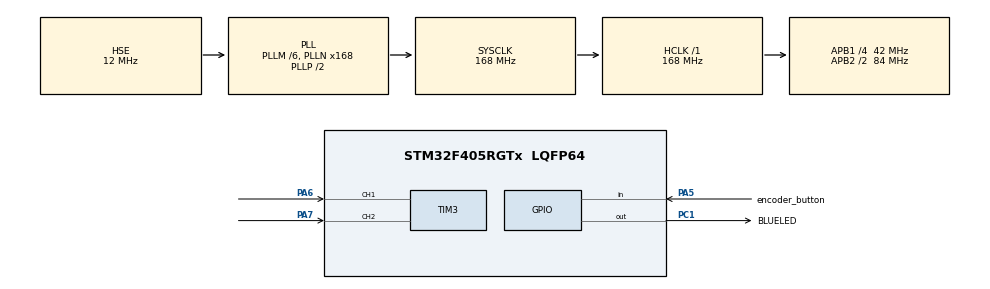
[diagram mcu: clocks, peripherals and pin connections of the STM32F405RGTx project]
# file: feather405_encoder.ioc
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Mcu.Family=STM32F4
Mcu.Name=STM32F405RGTx
Mcu.Package=LQFP64
NVIC.PriorityGroup=NVIC_PRIORITYGROUP_4
PA13.Mode=Serial_Wire
PA13.Signal=SYS_JTMS-SWDIO
PA14.Mode=Serial_Wire
PA14.Signal=SYS_JTCK-SWCLK
PA5.GPIO_Label=encoder_button
PA5.GPIO_PuPd=GPIO_PULLUP
PA5.Signal=GPIO_Input
PA6.Signal=S_TIM3_CH1
PA7.Signal=S_TIM3_CH2
PC1.GPIO_Label=BLUELED
PC1.Signal=GPIO_Output
PH0-OSC_IN.Mode=HSE-External-Oscillator
PH0-OSC_IN.Signal=RCC_OSC_IN
PH1-OSC_OUT.Mode=HSE-External-Oscillator
PH1-OSC_OUT.Signal=RCC_OSC_OUT
ProjectManager.HeapSize=0x200
ProjectManager.StackSize=0x400
ProjectManager.TargetToolchain=STM32CubeIDE
RCC.48MHZClocksFreq_Value=84000000
RCC.AHBFreq_Value=168000000
RCC.APB1CLKDivider=RCC_HCLK_DIV4
RCC.APB1Freq_Value=42000000
RCC.APB1TimFreq_Value=84000000
RCC.APB2CLKDivider=RCC_HCLK_DIV2
RCC.APB2Freq_Value=84000000
RCC.APB2TimFreq_Value=168000000
RCC.CortexFreq_Value=168000000
RCC.HCLKFreq_Value=168000000
RCC.HSE_VALUE=12000000
RCC.HSI_VALUE=16000000
RCC.LSE_VALUE=32768
RCC.PLLM=6
RCC.PLLN=168
RCC.PLLSourceVirtual=RCC_PLLSOURCE_HSE
RCC.SYSCLKFreq_VALUE=168000000
RCC.SYSCLKSource=RCC_SYSCLKSOURCE_PLLCLK
RCC.VCOOutputFreq_Value=336000000
SH.S_TIM3_CH1.0=TIM3_CH1,Encoder_Interface
SH.S_TIM3_CH2.0=TIM3_CH2,Encoder_Interface
TIM3.EncoderMode=TIM_ENCODERMODE_TI12
TIM3.IC1Polarity=TIM_ICPOLARITY_FALLING
TIM3.IC2Polarity=TIM_ICPOLARITY_FALLING
board=custom

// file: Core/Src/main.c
/* USER CODE BEGIN Header */
/**
  ******************************************************************************
  * @file           : main.c
  * @brief          : Main program body
  ******************************************************************************
  * @attention
  *
  * Copyright (c) 2023 STMicroelectronics.
  * All rights reserved.
  *
  * This software is licensed under terms that can be found in the LICENSE file
  * in the root directory of this software component.
  * If no LICENSE file comes with this software, it is provided AS-IS.
  *
  ******************************************************************************
  */
/* USER CODE END Header */
#include "main.h"

TIM_HandleTypeDef htim3;

void SystemClock_Config(void);
static void MX_GPIO_Init(void);
static void MX_TIM3_Init(void);

/* USER CODE BEGIN 0 */
int16_t counter=0;
/* USER CODE END 0 */

int main(void)
{

  /* MCU Configuration--------------------------------------------------------*/

  /* Reset of all peripherals, Initializes the Flash interface and the Systick. */
  HAL_Init();

  /* Configure the system clock */
  SystemClock_Config();

  /* Initialize all configured peripherals */
  MX_GPIO_Init();
  MX_TIM3_Init();
  /* USER CODE BEGIN 2 */
HAL_TIM_Encoder_Start(&htim3, TIM_CHANNEL_ALL);
  /* USER CODE END 2 */

  /* Infinite loop */
  /* USER CODE BEGIN WHILE */
  while (1)
  {
	  if(HAL_GPIO_ReadPin(encoder_button_GPIO_Port, encoder_button_Pin)==GPIO_PIN_SET){//https://www.youtube.com/watch?v=xqzWQgpqHmI
		  HAL_GPIO_WritePin(BLUELED_GPIO_Port, BLUELED_Pin, GPIO_PIN_RESET);
	  }else{
		  HAL_GPIO_WritePin(BLUELED_GPIO_Port, BLUELED_Pin, GPIO_PIN_SET);
	  }
	  counter=htim3.Instance->CNT;

    /* USER CODE END WHILE */

  }
}

void SystemClock_Config(void)
{
  RCC_OscInitTypeDef RCC_OscInitStruct = {0};
  RCC_ClkInitTypeDef RCC_ClkInitStruct = {0};

  /** Configure the main internal regulator output voltage
  */
  __HAL_RCC_PWR_CLK_ENABLE();
  __HAL_PWR_VOLTAGESCALING_CONFIG(PWR_REGULATOR_VOLTAGE_SCALE1);

  /** Initializes the RCC Oscillators according to the specified parameters
  * in the RCC_OscInitTypeDef structure.
  */
  RCC_OscInitStruct.OscillatorType = RCC_OSCILLATORTYPE_HSE;
  RCC_OscInitStruct.HSEState = RCC_HSE_ON;
  RCC_OscInitStruct.PLL.PLLState = RCC_PLL_ON;
  RCC_OscInitStruct.PLL.PLLSource = RCC_PLLSOURCE_HSE;
  RCC_OscInitStruct.PLL.PLLM = 6;
  RCC_OscInitStruct.PLL.PLLN = 168;
  RCC_OscInitStruct.PLL.PLLP = RCC_PLLP_DIV2;
  RCC_OscInitStruct.PLL.PLLQ = 4;
  if (HAL_RCC_OscConfig(&RCC_OscInitStruct) != HAL_OK)
  {
    Error_Handler();
  }

  /** Initializes the CPU, AHB and APB buses clocks
  */
  RCC_ClkInitStruct.ClockType = RCC_CLOCKTYPE_HCLK|RCC_CLOCKTYPE_SYSCLK
                              |RCC_CLOCKTYPE_PCLK1|RCC_CLOCKTYPE_PCLK2;
  RCC_ClkInitStruct.SYSCLKSource = RCC_SYSCLKSOURCE_PLLCLK;
  RCC_ClkInitStruct.AHBCLKDivider = RCC_SYSCLK_DIV1;
  RCC_ClkInitStruct.APB1CLKDivider = RCC_HCLK_DIV4;
  RCC_ClkInitStruct.APB2CLKDivider = RCC_HCLK_DIV2;

  if (HAL_RCC_ClockConfig(&RCC_ClkInitStruct, FLASH_LATENCY_5) != HAL_OK)
  {
    Error_Handler();
  }
}

static void MX_TIM3_Init(void)
{

  TIM_Encoder_InitTypeDef sConfig = {0};
  TIM_MasterConfigTypeDef sMasterConfig = {0};

  htim3.Instance = TIM3;
  htim3.Init.Prescaler = 0;
  htim3.Init.CounterMode = TIM_COUNTERMODE_UP;
  htim3.Init.Period = 65535;
  htim3.Init.ClockDivision = TIM_CLOCKDIVISION_DIV1;
  htim3.Init.AutoReloadPreload = TIM_AUTORELOAD_PRELOAD_DISABLE;
  sConfig.EncoderMode = TIM_ENCODERMODE_TI12;
  sConfig.IC1Polarity = TIM_ICPOLARITY_FALLING;
  sConfig.IC1Selection = TIM_ICSELECTION_DIRECTTI;
  sConfig.IC1Prescaler = TIM_ICPSC_DIV1;
  sConfig.IC1Filter = 0;
  sConfig.IC2Polarity = TIM_ICPOLARITY_FALLING;
  sConfig.IC2Selection = TIM_ICSELECTION_DIRECTTI;
  sConfig.IC2Prescaler = TIM_ICPSC_DIV1;
  sConfig.IC2Filter = 0;
  if (HAL_TIM_Encoder_Init(&htim3, &sConfig) != HAL_OK)
  {
    Error_Handler();
  }
  sMasterConfig.MasterOutputTrigger = TIM_TRGO_RESET;
  sMasterConfig.MasterSlaveMode = TIM_MASTERSLAVEMODE_DISABLE;
  if (HAL_TIMEx_MasterConfigSynchronization(&htim3, &sMasterConfig) != HAL_OK)
  {
    Error_Handler();
  }

}

static void MX_GPIO_Init(void)
{
  GPIO_InitTypeDef GPIO_InitStruct = {0};

  /* GPIO Ports Clock Enable */
  __HAL_RCC_GPIOH_CLK_ENABLE();
  __HAL_RCC_GPIOC_CLK_ENABLE();
  __HAL_RCC_GPIOA_CLK_ENABLE();
  __HAL_RCC_GPIOB_CLK_ENABLE();

  /*Configure GPIO pin Output Level */
  HAL_GPIO_WritePin(BLUELED_GPIO_Port, BLUELED_Pin, GPIO_PIN_RESET);

  /*Configure GPIO pin : BLUELED_Pin */
  GPIO_InitStruct.Pin = BLUELED_Pin;
  GPIO_InitStruct.Mode = GPIO_MODE_OUTPUT_PP;
  GPIO_InitStruct.Pull = GPIO_NOPULL;
  GPIO_InitStruct.Speed = GPIO_SPEED_FREQ_LOW;
  HAL_GPIO_Init(BLUELED_GPIO_Port, &GPIO_InitStruct);

  /*Configure GPIO pin : encoder_button_Pin */
  GPIO_InitStruct.Pin = encoder_button_Pin;
  GPIO_InitStruct.Mode = GPIO_MODE_INPUT;
  GPIO_InitStruct.Pull = GPIO_PULLUP;
  HAL_GPIO_Init(encoder_button_GPIO_Port, &GPIO_InitStruct);

  /*Configure GPIO pins : PB13 PB15 */
  GPIO_InitStruct.Pin = GPIO_PIN_13|GPIO_PIN_15;
  GPIO_InitStruct.Mode = GPIO_MODE_AF_PP;
  GPIO_InitStruct.Pull = GPIO_NOPULL;
  GPIO_InitStruct.Speed = GPIO_SPEED_FREQ_VERY_HIGH;
  GPIO_InitStruct.Alternate = GPIO_AF5_SPI2;
  HAL_GPIO_Init(GPIOB, &GPIO_InitStruct);

}

void Error_Handler(void)
{
  __disable_irq();
  while (1)
  {
  }
}
